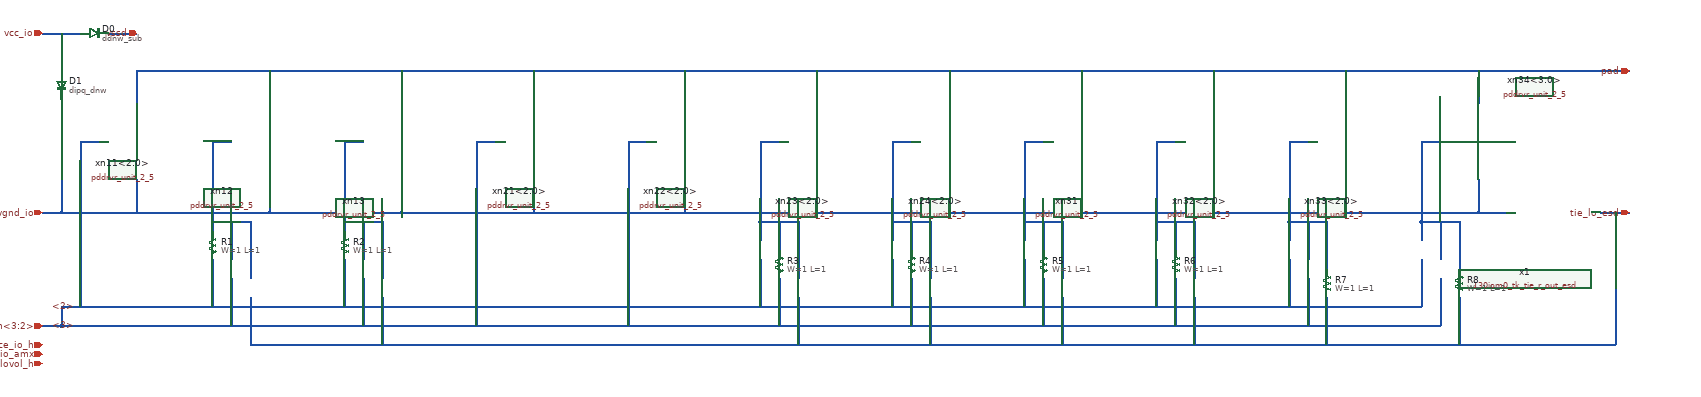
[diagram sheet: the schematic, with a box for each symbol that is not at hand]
v {xschem version=3.4.0 file_version=1.2
}
G {}
K {}
V {}
S {}
E {}
N 140 -780 220 -780 {
lab=vcc_io}
N 180 -780 180 -700 {
lab=vcc_io}
N 180 -640 180 -550 {
lab=vgnd_io}
N 280 -780 340 -780 {
lab=vssd}
N 340 -700 340 -630 {
lab=pad}
N 620 -700 620 -630 {
lab=pad}
N 900 -700 900 -630 {
lab=pad}
N 1180 -700 1180 -630 {
lab=pad}
N 1500 -700 1500 -630 {
lab=pad}
N 1780 -700 1780 -630 {
lab=pad}
N 2060 -700 2060 -630 {
lab=pad}
N 2340 -700 2340 -630 {
lab=pad}
N 2620 -700 2620 -630 {
lab=pad}
N 2900 -700 2900 -630 {
lab=pad}
N 3180 -700 3180 -630 {
lab=pad}
N 340 -700 3500 -700 {
lab=pad}
N 340 -470 340 -400 {
lab=vgnd_io}
N 620 -470 620 -400 {
lab=vgnd_io}
N 900 -470 900 -400 {
lab=vgnd_io}
N 1180 -470 1180 -400 {
lab=vgnd_io}
N 1500 -470 1500 -400 {
lab=vgnd_io}
N 1780 -470 1780 -400 {
lab=vgnd_io}
N 2060 -470 2060 -400 {
lab=vgnd_io}
N 2340 -470 2340 -400 {
lab=vgnd_io}
N 2620 -470 2620 -400 {
lab=vgnd_io}
N 2900 -470 2900 -400 {
lab=vgnd_io}
N 3180 -470 3180 -400 {
lab=vgnd_io}
N 340 -400 620 -400 {
lab=vgnd_io}
N 620 -400 900 -400 {
lab=vgnd_io}
N 900 -400 1180 -400 {
lab=vgnd_io}
N 1180 -400 1500 -400 {
lab=vgnd_io}
N 1500 -400 1780 -400 {
lab=vgnd_io}
N 1780 -400 2060 -400 {
lab=vgnd_io}
N 2060 -400 2340 -400 {
lab=vgnd_io}
N 2340 -400 2620 -400 {
lab=vgnd_io}
N 2620 -400 2900 -400 {
lab=vgnd_io}
N 2900 -400 3180 -400 {
lab=vgnd_io}
N 3180 -400 3240 -400 {
lab=vgnd_io}
N 180 -550 180 -400 {
lab=vgnd_io}
N 180 -400 340 -400 {
lab=vgnd_io}
N 140 -400 180 -400 {
lab=vgnd_io}
N 3440 -400 3500 -400 {
lab=tie_lo_esd}
N 220 -550 260 -550 {
lab=pd_h<3:2>}
N 180 -200 180 -160 {
lab=pd_h<3:2>}
N 140 -160 180 -160 {
lab=pd_h<3:2>}
N 220 -550 220 -200 {
lab=pd_h<3:2>}
N 500 -550 540 -550 {
lab=#net1}
N 500 -550 500 -360 {
lab=#net1}
N 500 -300 500 -200 {
lab=pd_h<3:2>}
N 540 -260 540 -160 {
lab=pd_h<3:2>}
N 500 -380 580 -380 {
lab=#net1}
N 580 -380 580 -260 {
lab=#net1}
N 540 -380 540 -300 {
lab=#net1}
N 580 -220 580 -120 {
lab=tie_lo_esd}
N 580 -120 3470 -120 {
lab=tie_lo_esd}
N 3470 -400 3470 -120 {
lab=tie_lo_esd}
N 780 -300 780 -200 {
lab=pd_h<3:2>}
N 820 -260 820 -160 {
lab=pd_h<3:2>}
N 780 -380 860 -380 {
lab=#net2}
N 860 -380 860 -260 {
lab=#net2}
N 820 -380 820 -300 {
lab=#net2}
N 860 -220 860 -120 {
lab=tie_lo_esd}
N 780 -550 780 -360 {
lab=#net2}
N 780 -550 820 -550 {
lab=#net2}
N 1060 -550 1100 -550 {
lab=pd_h<3:2>}
N 1380 -550 1420 -550 {
lab=pd_h<3:2>}
N 1060 -550 1060 -160 {
lab=pd_h<3:2>}
N 1380 -550 1380 -160 {
lab=pd_h<3:2>}
N 1660 -300 1660 -200 {
lab=pd_h<3:2>}
N 1700 -260 1700 -160 {
lab=pd_h<3:2>}
N 1660 -380 1740 -380 {
lab=#net3}
N 1740 -380 1740 -260 {
lab=#net3}
N 1740 -220 1740 -120 {
lab=tie_lo_esd}
N 1660 -380 1660 -340 {
lab=#net3}
N 1700 -380 1700 -320 {
lab=#net3}
N 1660 -550 1700 -550 {
lab=#net3}
N 1660 -550 1660 -380 {
lab=#net3}
N 1940 -550 1940 -380 {
lab=#net4}
N 2220 -550 2220 -380 {
lab=#net5}
N 2500 -550 2500 -380 {
lab=#net6}
N 1940 -550 1980 -550 {
lab=#net4}
N 2220 -550 2260 -550 {
lab=#net5}
N 2500 -550 2540 -550 {
lab=#net6}
N 1940 -300 1940 -200 {
lab=pd_h<3:2>}
N 1980 -260 1980 -160 {
lab=pd_h<3:2>}
N 1940 -380 2020 -380 {
lab=#net4}
N 2020 -380 2020 -260 {
lab=#net4}
N 2020 -220 2020 -120 {
lab=tie_lo_esd}
N 1940 -380 1940 -340 {
lab=#net4}
N 1980 -380 1980 -320 {
lab=#net4}
N 2220 -300 2220 -200 {
lab=pd_h<3:2>}
N 2260 -260 2260 -160 {
lab=pd_h<3:2>}
N 2220 -380 2300 -380 {
lab=#net5}
N 2300 -380 2300 -260 {
lab=#net5}
N 2300 -220 2300 -120 {
lab=tie_lo_esd}
N 2220 -380 2220 -340 {
lab=#net5}
N 2260 -380 2260 -320 {
lab=#net5}
N 2500 -300 2500 -200 {
lab=pd_h<3:2>}
N 2540 -260 2540 -160 {
lab=pd_h<3:2>}
N 2500 -380 2580 -380 {
lab=#net6}
N 2580 -380 2580 -260 {
lab=#net6}
N 2580 -220 2580 -120 {
lab=tie_lo_esd}
N 2500 -380 2500 -340 {
lab=#net6}
N 2540 -380 2540 -320 {
lab=#net6}
N 2780 -550 2820 -550 {
lab=#net7}
N 3060 -550 3100 -550 {
lab=#net8}
N 2780 -550 2780 -380 {
lab=#net7}
N 3060 -550 3060 -380 {
lab=#net8}
N 2780 -300 2780 -200 {
lab=pd_h<3:2>}
N 2820 -260 2820 -160 {
lab=pd_h<3:2>}
N 2780 -380 2860 -380 {
lab=#net7}
N 2860 -220 2860 -120 {
lab=tie_lo_esd}
N 2780 -380 2780 -340 {
lab=#net7}
N 2820 -380 2820 -300 {
lab=#net7}
N 2860 -380 2860 -280 {}
N 3060 -300 3060 -200 {
lab=pd_h<3:2>}
N 3100 -260 3100 -160 {
lab=pd_h<3:2>}
N 3060 -380 3140 -380 {
lab=#net7}
N 3140 -220 3140 -120 {
lab=tie_lo_esd}
N 3060 -380 3060 -340 {
lab=#net7}
N 3100 -380 3100 -300 {
lab=#net7}
N 3140 -380 3140 -280 {}
N 180 -200 3060 -200 {
lab=pd_h<3:2>}
N 180 -160 3100 -160 {
lab=pd_h<3:2>}
C {devices/ipin.sym} 140 -780 0 0 {name=p4 lab=vcc_io}
C {devices/iopin.sym} 340 -780 0 0 {name=p5 lab=vssd}
C {devices/ipin.sym} 140 -400 0 0 {name=p6 lab=vgnd_io}
C {sky130_fd_pr/diode.sym} 180 -670 0 0 {name=D1
model=dipq_dnw
area=1.566k}
C {sky130_fd_pr/lvsdiode.sym} 250 -780 3 0 {name=D0
model=ddnw_sub
area=1.791k}
C {pddrvr_unit_2_5.sym} 340 -510 0 0 {name=xn11<2:0>}
C {pddrvr_unit_2_5.sym} 620 -510 0 0 {name=xn12}
C {pddrvr_unit_2_5.sym} 900 -510 0 0 {name=xn13}
C {pddrvr_unit_2_5.sym} 1180 -510 0 0 {name=xn21<2:0>}
C {pddrvr_unit_2_5.sym} 1500 -510 0 0 {name=xn22<2:0>}
C {pddrvr_unit_2_5.sym} 1780 -510 0 0 {name=xn23<2:0>}
C {pddrvr_unit_2_5.sym} 2060 -510 0 0 {name=xn24<2:0>}
C {pddrvr_unit_2_5.sym} 2340 -510 0 0 {name=xn31}
C {pddrvr_unit_2_5.sym} 2620 -510 0 0 {name=xn32<2:0>}
C {pddrvr_unit_2_5.sym} 2900 -510 0 0 {name=xn33<2:0>}
C {pddrvr_unit_2_5.sym} 3180 -510 0 0 {name=xn34<3:0>}
C {devices/iopin.sym} 3500 -700 0 0 {name=p1 lab=pad}
C {devices/ipin.sym} 140 -160 0 0 {name=p2 lab=pd_h<3:2>}
C {devices/ipin.sym} 140 -120 0 0 {name=p3 lab=force_io_h}
C {devices/ipin.sym} 140 -100 0 0 {name=p7 lab=vssio_amx}
C {devices/ipin.sym} 140 -80 0 0 {name=p8 lab=force_lovol_h}
C {devices/noconn.sym} 140 -80 2 0 {name=l6}
C {devices/noconn.sym} 140 -100 2 0 {name=l1}
C {devices/noconn.sym} 140 -120 2 0 {name=l2}
C {devices/ipin.sym} 3500 -400 2 0 {name=p9 lab=tie_lo_esd}
C {130iom0_tk_tie_r_out_esd.sym} 3390 -400 0 0 {name=x1}
C {devices/lab_wire.sym} 210 -160 0 0 {name=p10 sig_type=std_logic lab=<3>}
C {devices/lab_wire.sym} 210 -200 0 0 {name=p11 sig_type=std_logic lab=<2>}
C {sky130_fd_pr/res_generic_m2.sym} 500 -330 0 0 {name=R1
W=1
L=1
model=res_generic_m2
mult=1}
C {devices/noconn.sym} 540 -260 1 0 {name=l3}
C {devices/noconn.sym} 540 -300 3 0 {name=l4}
C {devices/noconn.sym} 580 -220 1 0 {name=l5}
C {devices/noconn.sym} 580 -260 3 0 {name=l7}
C {sky130_fd_pr/res_generic_m2.sym} 780 -330 0 0 {name=R2
W=1
L=1
model=res_generic_m2
mult=1}
C {devices/noconn.sym} 820 -260 1 0 {name=l8}
C {devices/noconn.sym} 820 -300 3 0 {name=l9}
C {devices/noconn.sym} 860 -220 1 0 {name=l10}
C {devices/noconn.sym} 860 -260 3 0 {name=l11}
C {sky130_fd_pr/res_generic_m2.sym} 1700 -290 0 0 {name=R3
W=1
L=1
model=res_generic_m2
mult=1}
C {devices/noconn.sym} 1660 -300 1 0 {name=l12}
C {devices/noconn.sym} 1660 -340 3 0 {name=l13}
C {devices/noconn.sym} 1740 -220 1 0 {name=l14}
C {devices/noconn.sym} 1740 -260 3 0 {name=l15}
C {sky130_fd_pr/res_generic_m2.sym} 1980 -290 0 0 {name=R4
W=1
L=1
model=res_generic_m2
mult=1}
C {devices/noconn.sym} 1940 -300 1 0 {name=l16}
C {devices/noconn.sym} 1940 -340 3 0 {name=l17}
C {devices/noconn.sym} 2020 -220 1 0 {name=l18}
C {devices/noconn.sym} 2020 -260 3 0 {name=l19}
C {sky130_fd_pr/res_generic_m2.sym} 2260 -290 0 0 {name=R5
W=1
L=1
model=res_generic_m2
mult=1}
C {devices/noconn.sym} 2220 -300 1 0 {name=l20}
C {devices/noconn.sym} 2220 -340 3 0 {name=l21}
C {devices/noconn.sym} 2300 -220 1 0 {name=l22}
C {devices/noconn.sym} 2300 -260 3 0 {name=l23}
C {sky130_fd_pr/res_generic_m2.sym} 2540 -290 0 0 {name=R6
W=1
L=1
model=res_generic_m2
mult=1}
C {devices/noconn.sym} 2500 -300 1 0 {name=l24}
C {devices/noconn.sym} 2500 -340 3 0 {name=l25}
C {devices/noconn.sym} 2580 -220 1 0 {name=l26}
C {devices/noconn.sym} 2580 -260 3 0 {name=l27}
C {sky130_fd_pr/res_generic_m2.sym} 2860 -250 0 0 {name=R7
W=1
L=1
model=res_generic_m2
mult=1}
C {devices/noconn.sym} 2780 -300 1 0 {name=l28}
C {devices/noconn.sym} 2780 -340 3 0 {name=l29}
C {devices/noconn.sym} 2820 -260 1 0 {name=l30}
C {devices/noconn.sym} 2820 -300 3 0 {name=l31}
C {sky130_fd_pr/res_generic_m2.sym} 3140 -250 0 0 {name=R8
W=1
L=1
model=res_generic_m2
mult=1}
C {devices/noconn.sym} 3060 -300 1 0 {name=l32}
C {devices/noconn.sym} 3060 -340 3 0 {name=l33}
C {devices/noconn.sym} 3100 -260 1 0 {name=l34}
C {devices/noconn.sym} 3100 -300 3 0 {name=l35}
